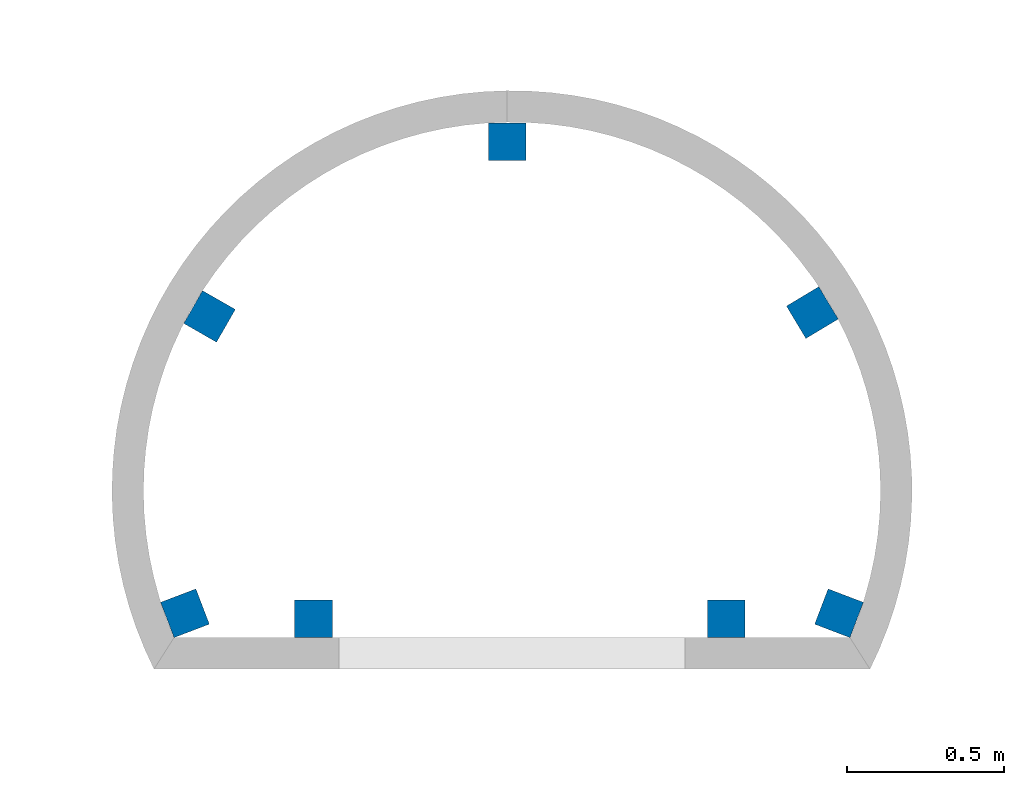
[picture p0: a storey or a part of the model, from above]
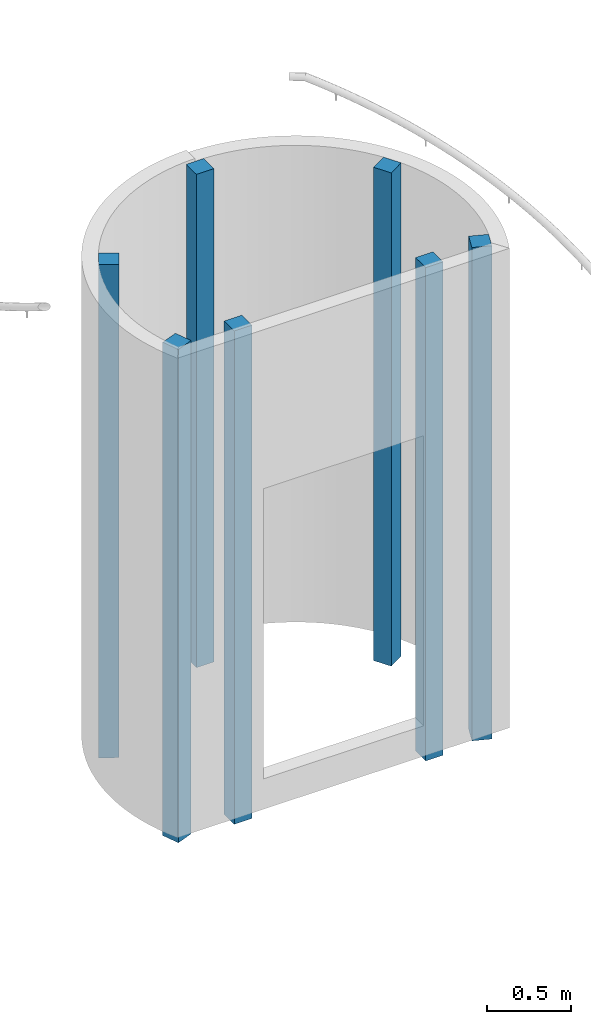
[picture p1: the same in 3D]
Properties of the parts of a building model (IFC4)

# File
Description: ViewDefinition [Design_Transfer_View, QuantityTakeOffAddOnView, SpaceBoundary2ndLevelAddOnView], ExchangeRequirement [Architecture], Option [Elements to export: Visible elements (on all stories)], Option [Partial Structure Display: Entire Model], Option [IFC Domain: All], Option [Structural Function: All Elements], Option [Convert Grid elements: On], Option [Convert IFC Annotations and Archicad 2D elements: Off], Option [Convert 2D symbols of Doors and Windows: Off], Option [Export geometries that Participates in Collision Detection only: Off], Option [Split complex elements: Off], Option [Material Preservation: Explode where necessary], Option [Elements in Solid Element Operations: Extruded/revolved], Option [Elements with junctions: Extruded/revolved without junctions], Option [IFC Model position: Survey Point and Project Origin], Option [Curtain Wall export mode: Container Element], Option [Railing export mode: Single Element], Option [Stair export mode: Container Element], Option [Properties To Export: All properties], Option [Space containment: On], Option [IFC Domain For Space Containment: All], Option [Geometry to type objects: Off], Option [Element Properties: Off], Option [Building Material Properties: Off], Option [Element Parameters: Off], Option [Component Parameters: Off], Option [IFC Base Quantities: On], Option [Door Window Parameters: On], Option [IFC Space boundaries: On], Option [Archicad Zone Categories as IFC Space classification data: Off], Option [Element Classifications: Off]
File name: C:\Users\micel\OneDrive\Dokumenty\ŠKOLA\!!4.LS!!\BAKALÁŘKA\Publikace\Nová složka\LES24-PST-ZZ-M3-Vyrobky.ifc
Time: 2024-05-22T15:31:04
Author: Architect
Organization: Building Designer Office
Written by: DDS_IFC v3.0
Made in: IFC file generated by Graphisoft Archicad 27.0.0 CZE FULL Windows version (IFC add-on version: 3001 CZE FULL).
Authorization: The authorising person

# IfcProject, Univerzitní lezecké centrum
Description: BIM projekt - bakalářská práce

# IfcSite, Exteriér
RefLatitude: 50, 1, 18, 339575; RefLongitude: 15, 46, 11, 568244; RefElevation: 221783 mm
Qto_SiteBaseQuantities - GrossPerimeter: 0 mm; GrossArea: 3562 m2

# IfcBuilding, Univerzitní lezecké centrum
Qto_BuildingBaseQuantities - GrossFloorArea: 0 m2

# IfcBuildingStorey (6)
In: Univerzitní lezecké centrum
Qto_BuildingStoreyBaseQuantities - GrossFloorArea: 0 m2
Name | Elevation (mm) | NetHeight (mm) = GrossHeight (mm)
2.NP | 3200 | 3200
4.NP | 9600 | 3200
3.NP | 6400 | 3200
Střecha | 12800 | 8000
1.NP | 0 | 3200
1.PP | -3350 | 3350

# IfcBeam: Benátské žaluzie 27 (14)
In: 1.NP
Type - PredefinedType: BEAM
Description: Venkovní žaluzie poháněné elektrickým motorkem, ovládání pomocí vypínače uvnitř prostoru lobby s posezením, lamely tvaru "C" o velikosti 65 mm, vodící lanka zajišťují směr pohybu lamel, barva černá Montováno do purenitových předomítkových boxů
Pset_BeamCommon - Status: EXISTING
Pset_ManufacturerOccurrence - AcquisitionDate: DD.MM.RRRR

# IfcBeam: Kačírková lišta 220 x 165 (9)
In: Střecha
Type - PredefinedType: BEAM
Description: Kačírková lišta - hliník tl. 2 mm, perforovaný pro umožnění průtoku vody, RAL 9007, úhel 78 stupňů, R.Š. 505 mm; Material: Hliníková kačírková lišta (2)
Pset_ManufacturerOccurrence - AcquisitionDate: DD.MM.RRRR
Qto_BeamBaseQuantities - CrossSectionArea: 0.00082048 m2
Pset_BeamCommon - Span: 4500 mm; Slope: 0 deg; IsExternal: no; Status: EXISTING; LoadBearing: yes; Reference: Kačírková lišta 220 x 165
Name | Length (mm) | OuterSurfaceArea (m2) | GrossSurfaceArea (m2) = NetSurfaceArea (m2) | GrossVolume (m3) = NetVolume (m3)
ZV08 | 4714.88 | 3.7068 | 3.70844 | 0.00387202
ZV08 | 5462.36 | 4.29446 | 4.2961 | 0.00448587
ZV08 | 5538.15 | 4.35405 | 4.35569 | 0.00454811
ZV08 | 10989.2 | 8.63963 | 8.64127 | 0.00902472
ZV08 | 16195.3 | 12.7326 | 12.7342 | 0.0133001
ZV08 | 16295.7 | 12.8116 | 12.8132 | 0.0133826
ZV08 | 5538.09 | 4.354 | 4.35564 | 0.00454806
ZV08 | 5460.56 | 4.29304 | 4.29468 | 0.00448439
ZV08 | 4712.68 | 3.70507 | 3.70671 | 0.00387021

# IfcBeam: Kačírková lišta vysoká 220 x 225, ZV07
In: Střecha
Type - PredefinedType: BEAM
Description: Kačírková lišta - hliník tl. 2 mm, perforovaný pro umožnění průtoku vody, RAL 9007, úhel 78 stupňů, R.Š. 565 mm; Material: Hliníková kačírková lišta (2)
Pset_BeamCommon - Span: 4500 mm; Slope: 0 deg; IsExternal: no; Status: EXISTING; LoadBearing: yes; Reference: Kačírková lišta vysoká 220 x 225
Pset_ManufacturerOccurrence - AcquisitionDate: DD.MM.RRRR
Qto_BeamBaseQuantities - Length: 16295 mm; CrossSectionArea: 0.00094048 m2; OuterSurfaceArea: 14.7664 m2; GrossSurfaceArea: 14.7683 m2; GrossVolume: 0.0153374 m3; NetSurfaceArea: 14.7683 m2; NetVolume: 0.0153374 m3

# IfcBeam: Kotvící bod záchytného systému 80 x 590 (12)
In: Střecha
Type - PredefinedType: BEAM
Description: Nerezový kotvicí bod pro ocelové konstrukce. Průměr sloupku je 12 mm. Instalace do předvrtaného otvoru v nosníku pomocí kontramatky. Pro použití jako koncový a zlomový bod v systémech s nerezovým lanem je nutné jej při délkách větších než 100 mm doplnit ztužující trubkou, délka kotvy 600 m Oky protaženo záchytné ocelové lano, délka 50 m; Material: Ocel - nerez (2)
Pset_ManufacturerOccurrence - AcquisitionDate: DD.MM.RRRR
Qto_BeamBaseQuantities - Length: 20 mm; CrossSectionArea: 0.0124075 m2; GrossVolume: 0.000246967 m3
Pset_BeamCommon - Span: 4500 mm; Slope: 0 deg; IsExternal: no; Status: EXISTING; LoadBearing: yes; Reference: Kotvící bod záchytného systému 80 x 590
Name | OuterSurfaceArea (m2) | GrossSurfaceArea (m2) = NetSurfaceArea (m2) | NetVolume (m3)
11 x OV27 | 0.0291858 | 0.0540008 | 0.000246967
OV27 | 0.029097 | 0.053912 | 0.000246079

# IfcBeam: Kruhová střešní vpusť 27 (2)
In: 3.NP
Type - PredefinedType: BEAM
Description: Vodorovná vpusť s integrovanou manžetou z TPO fólie, typ TW 110 V - DN 100 mm, vodorovné odvodní potrubí, tělo vpusti z polyamid PA6 s ochranným košem rozměry viz schéma: a=330, b=200, c=130, d=157, e=25 , f=238, g=47 mm
Reference - Referenční výrobek: https://www.topwet.cz/vodorovna-stresni-vpust-s-integrovanou-pvc-manzetou-p7
Pset_ManufacturerOccurrence - AcquisitionDate: DD.MM.RRRR
Pset_BeamCommon - Status: EXISTING

# IfcBeam: L profil 90x90x7 90 x 90 (8)
In: Střecha
Type - PredefinedType: BEAM
Description: L úhelník 90x90x7 mm - nerezový úhelník pro uchycení střešních oken, okno kotveno z bočních stran, úhelník kotven k betonové vrstvě na trapézovém plechu; Material: Ocel - nerez
Pset_BeamCommon - Span: 4500 mm; Slope: 12 deg; IsExternal: no; Status: EXISTING; LoadBearing: yes; Reference: L profil 90x90x7 90 x 90
Pset_ManufacturerOccurrence - AcquisitionDate: DD.MM.RRRR
Qto_BeamBaseQuantities - Length: 2019.13 mm; CrossSectionArea: 0.001211 m2; OuterSurfaceArea: 0.72 m2; GrossSurfaceArea: 0.722422 m2; GrossVolume: 0.002422 m3; NetSurfaceArea: 0.722422 m2; NetVolume: 0.002422 m3

# IfcBeam: Purenitový podomítkový box 195 x 302 (14)
In: 1.NP
Type - PredefinedType: BEAM
Description: Předomítkový purenitový box pro montáž venkovních žaluzií, tloušťka komplet purenitu 20 mm, R.Š. 505 mm, varianta pro omítnutí, kotveno montážní konzolou - úhleníkem L 100x100 mm (v rámci dodávky boxu), délka boxu 1250 mm; Material: Tepelná izolace - purenit (2), Hliník (2)
Pset_BeamCommon - Span: 4500 mm; Slope: 0 deg; IsExternal: no; Status: EXISTING; LoadBearing: yes; Reference: Purenitový podomítkový box 195 x 302
Pset_ManufacturerOccurrence - AcquisitionDate: DD.MM.RRRR
Qto_BeamBaseQuantities - Length: 1250 mm; CrossSectionArea: 0.0103491 m2; GrossVolume: 0.0129364 m3
Name | OuterSurfaceArea (m2) | GrossSurfaceArea (m2) = NetSurfaceArea (m2) | NetVolume (m3)
OV10 | 1.14941 | 1.17011 | 0.0117203
OV10 | 1.14885 | 1.16955 | 0.0117197
OV10 | 1.14929 | 1.16999 | 0.0117202
OV10 | 1.14908 | 1.16978 | 0.0117201
OV10 | 1.14916 | 1.16986 | 0.01172
OV10 | 1.14858 | 1.16928 | 0.0117195
OV10 | 1.14865 | 1.16935 | 0.0117195
OV10 | 1.14898 | 1.16968 | 0.0117198
OV10 | 1.14879 | 1.16949 | 0.0117197
OV10 | 1.14884 | 1.16953 | 0.0117198
OV10 | 1.14853 | 1.16923 | 0.0117195
OV10 | 1.14892 | 1.16962 | 0.0117198
OV10 | 1.14868 | 1.16938 | 0.0117196
OV10 | 1.14905 | 1.16975 | 0.0117199

# IfcBeam: Stojan na kola 02 27 (5)
In: 1.PP
Type - PredefinedType: BEAM
Description: Nerezový stojan na kola, sloupky zabetonovány pod zámkovou dlažbou, na 6 kol
Pset_BeamCommon - Status: EXISTING
Pset_ManufacturerOccurrence - AcquisitionDate: DD.MM.RRRR

# IfcBeam: Tlakový hasicí přístroj 24 (20)
Type - PredefinedType: BEAM
Description: Hasící přístroj 21A - práškový, objem hasiva 6kg, rozměry 190x530, s držákem a manometrem, zavěšený na zdi 600 mm nad zemí
Pset_BeamCommon - Status: EXISTING
Pset_ManufacturerOccurrence - AcquisitionDate: DD.MM.RRRR
Name | In
5 x OV01 | 1.PP
4 x OV01 | 1.NP
5 x OV01 | 2.NP
3 x OV01 | 3.NP
3 x OV01 | 4.NP

# IfcBeam: Zrcadlo 27 (2)
In: 1.PP
Type - PredefinedType: BEAM
Pset_ManufacturerOccurrence - AcquisitionDate: DD.MM.RRRR
Pset_BeamCommon - Status: EXISTING

# IfcBeam: Žebřík s klecí 24, ZV05
In: Střecha
Type - PredefinedType: BEAM
Description: Provozní žebřík pro přístup na pultovou střechu objektu, opatřen plošinou se zábradlím, výška žebříku vyšší než 3,0 m --> zádržný systém viz ZV05, vzdálenost příčlí 300 mm, rozteč štěřín 550 mm, návrh dle ČSN 74 3282 Pevné kovové žebříky pro stavby Ževřík kotven opřen o podlahu a kotven do svislé železobetonové stěny skrze systémové kotvy pro zamezení vzniku tepelných mostů
Pset_BeamCommon - Status: EXISTING
Pset_ManufacturerOccurrence - AcquisitionDate: DD.MM.RRRR

# IfcBuildingElementProxy: Lavice 24 (12)
Pset_BuildingElementProxyCommon - Status: EXISTING
Name | In | Description
8 x OV04 | 1.PP | Kovová lavice (š.d.v.) 450x1500x400 mm, dřevotřísková deska bílá lesklá s abs hranou, tloušťka desky 25 mm
2 x OV05 | 2.NP | Kovová lavice (š.d.v.) 450x1250x400 mm, dřevotřísková deska bílá lesklá s abs hranou, tloušťka desky 25 mm
2 x OV04 | 2.NP | Kovová lavice (š.d.v.) 450x1500x400 mm, dřevotřísková deska bílá lesklá s abs hranou, tloušťka desky 25 mm

# IfcBuildingElementProxy: Okap 27 (2)
In: Střecha
Description: Žlab - obdélníkový přůřez 150x200 mm, pozinkovaný lakovaný RAL 9007, lakované pozinkované háky RAL 9007 po délce 1 m
Pset_BuildingElementProxyCommon - Status: EXISTING

# IfcBuildingElementProxy: Okapová roura 27 (2)
In: Střecha
Description: Odvodňovací svod - čtvercový přůřez DN150 mm, pozinkovaný, délka 3,0 m, lakovaný RAL 9007, lakované pozinkované kotvy RAL 9007 po výšce 1 m a 0,5 m od spodního nebo vrchního ukončení svodu, kotva R.Š. 640 mm
Pset_BuildingElementProxyCommon - Status: EXISTING

# IfcBuildingElementProxy: Popelnice 27 (3)
In: 1.NP
Pset_BuildingElementProxyCommon - Status: EXISTING

# IfcBuildingElementProxy: Skříňky 24 (64)
Description: Kovová šatní skříňka, 300x400x2050 mm, otevíravé jednokřídlé dveře, větrání z čelní a zadní strany, se zámkem na klíč a žeton/10 kč, barva modrá
Pset_BuildingElementProxyCommon - Status: EXISTING
Name | In
20 x OV02 | 1.PP
20 x OV03 | 1.PP
12 x OV02 | 2.NP
12 x OV03 | 2.NP

# IfcBuildingElementProxy: Výtah 24, OV26
In: 1.NP
Description: Výtah s definováním přejezdu dole i nahoře by byl předmětem speciální dokumentace a konfigurace výtahového balíčku, který je v tomto případě kompletně specifický, nosné profily z nerezové oceli kotvené z boku do schodišťových ramen nesou opláštění z hliníku, uvinitř složeného kruhového prostoru by se nacházel výtah s velikostí min 1600x900 mm, aby mohl obsluhovat osoby se sníženou schopností pohybu, výtah obsluhuje všechna podlaží
Pset_BuildingElementProxyCommon - Status: EXISTING

# IfcColumn: Nerez ocel D50, ZV04
In: 4.NP
Type - PredefinedType: COLUMN
Description: Pevný zajišťovací systém pro provozní žebřík ZV05, pohyb zachycovače pádu zajištěn pomocí kolejnice s karabinou, provedeno dle ČSN EN 353-1+A1 Prostředky ochrany osob proti pádu - Pohyblivé zachycovače pádu vetně zajišťovacího vedení - část1, umístěn uprostřed příčlí žebříku; Material: Nerez ocel
Pset_ManufacturerOccurrence - AcquisitionDate: DD.MM.RRRR
Qto_ColumnBaseQuantities - Length: 3700 mm; CrossSectionArea: 0.00196351 m2; OuterSurfaceArea: 0.57458 m2; GrossSurfaceArea: 0.57833 m2; GrossVolume: 0.00693755 m3; NetSurfaceArea: 0 m2; NetVolume: 0.00693755 m3
Pset_ColumnCommon - Slope: 90 deg; Status: EXISTING; LoadBearing: yes; Reference: Nerez ocel D50

# IfcColumn: Uživatelský profil 120 x 120 (35)
Type - PredefinedType: COLUMN
Material: OBECNÉ - HRUBÉ STAVEBNÍ KONSTRUKCE
Pset_ColumnCommon - Slope: 90 deg; Status: EXISTING; LoadBearing: yes; Reference: Uživatelský profil 120 x 120
Pset_ManufacturerOccurrence - AcquisitionDate: DD.MM.RRRR
Qto_ColumnBaseQuantities - CrossSectionArea: 0.0144 m2; NetSurfaceArea: 0 m2
Name | In | Length (mm) | OuterSurfaceArea (m2) | GrossSurfaceArea (m2) | GrossVolume (m3) = NetVolume (m3)
S006 | 1.PP | 3450 | 1.58301 | 1.59741 | 0.0496634
S006 | 1.PP | 3450 | 1.64053 | 1.65493 | 0.0496776
S007 | 1.PP | 3450 | 1.656 | 1.6704 | 0.04968
S006 | 1.PP | 3450 | 1.656 | 1.6704 | 0.04968
S008 | 1.PP | 3450 | 1.656 | 1.6704 | 0.04968
S006 | 1.PP | 3450 | 1.24177 | 1.25617 | 0.0496663
S006 | 1.PP | 3450 | 1.24176 | 1.25616 | 0.0496656
S006 | 1.NP | 3200 | 1.43284 | 1.46162 | 0.0460389
S006 | 1.NP | 3200 | 1.536 | 1.5648 | 0.04608
S006 | 1.NP | 3200 | 1.52165 | 1.55045 | 0.0460777
S007 | 1.NP | 3200 | 1.536 | 1.5648 | 0.04608
S006 | 1.NP | 3200 | 1.15178 | 1.18057 | 0.0460668
S006 | 1.NP | 3200 | 1.15181 | 1.1806 | 0.0460684
S008 | 1.NP | 3200 | 1.536 | 1.5648 | 0.04608
S006 | 2.NP | 3200 | 1.43282 | 1.4616 | 0.0460389
S006 | 2.NP | 3200 | 1.536 | 1.5648 | 0.04608
S007 | 2.NP | 3200 | 1.536 | 1.5648 | 0.04608
S008 | 2.NP | 3200 | 1.536 | 1.5648 | 0.04608
S006 | 2.NP | 3200 | 1.15197 | 1.18076 | 0.0460783
S006 | 2.NP | 3200 | 1.15195 | 1.18075 | 0.046077
S006 | 2.NP | 3200 | 1.52165 | 1.55045 | 0.0460777
S006 | 3.NP | 3200 | 1.536 | 1.5648 | 0.04608
S006 | 3.NP | 3200 | 1.43274 | 1.46152 | 0.0460391
S006 | 3.NP | 3200 | 1.52165 | 1.55045 | 0.0460777
S007 | 3.NP | 3200 | 1.536 | 1.5648 | 0.04608
2 x S006 | 3.NP | 3200 | 1.15178 | 1.18057 | 0.0460666
S008 | 3.NP | 3200 | 1.536 | 1.5648 | 0.04608
2 x S006 | 4.NP | 2700 | 0.971812 | 1.0006 | 0.0388687
S006 | 4.NP | 2700 | 1.23888 | 1.26767 | 0.038867
S006 | 4.NP | 2700 | 1.28389 | 1.31269 | 0.0388781
S006 | 4.NP | 2700 | 1.296 | 1.3248 | 0.03888
S007 | 4.NP | 2700 | 1.296 | 1.3248 | 0.03888
S008 | 4.NP | 2700 | 1.296 | 1.3248 | 0.03888

# IfcCovering: Oplechování atiky 569 x 114, KV01
In: 4.NP
Type - PredefinedType: CEILING
Description: Oplechování atiky pozinkovaným lakovaným plechem, tl. 0,6 mm, R.Š. 770mm, délka 26, 389 m, uchyceno za zatahovací plechy - kotvení bez perforace, barva RAL9007, svislé drážky v obloucích dle zkušenosti provádění dodavatele; Material: Hliník
Pset_CoveringCommon - Status: EXISTING
Pset_ManufacturerOccurrence - AcquisitionDate: DD.MM.RRRR
Qto_CoveringBaseQuantities - Width: 568.723 mm; GrossArea: 14.3441 m2; NetArea: 0 m2

# IfcCovering: Závětrná lišta 174 x 60 (2)
In: Střecha
Type - PredefinedType: CEILING
Description: Závětrná lišta z poplastovaného plechu z PVC, šedá, pro ukončení povlakové hydroizolace na pultové střeše, izolace k liště napojena horkovzdušným svarem, RAL 9007, tl. 1 mm; Material: Hliník, Hydroizolace - TPO fólie
Pset_ManufacturerOccurrence - AcquisitionDate: DD.MM.RRRR
Pset_CoveringCommon - IsExternal: no; Status: EXISTING
Qto_CoveringBaseQuantities - Width: 174.227 mm; GrossArea: 1.39096 m2; NetArea: 1.39096 m2

# IfcCurtainWall: Typ lehkého obvodového pláště (2)
In: 3.NP
Description: Lehký obvodový plášť, výška 2500, délka 4500 mm, zasklení bezpečnostním sklem, barva rámu RAL 6019, otočné dveře uprostřed modulu
Pset_CurtainWallCommon - Status: EXISTING
Pset_ManufacturerOccurrence - AcquisitionDate: DD.MM.RRRR
Qto_CurtainWallQuantities - Width: 300 mm; Length: 4500.17 mm
Name | Height (mm) | GrossSideArea (m2) = NetSideArea (m2)
LOP04 | 2000 | 9.00033
LOP06 | 2500 | 11.2504

# IfcDiscreteAccessory: Vnitřní malba, OV07
In: 4.NP
Description: Logo univerzity Pardubice - dle výrobní dokumentace dodavatele; Material: Vnitřní malba
Pset_ManufacturerOccurrence - AcquisitionDate: DD.MM.RRRR
Pset_ElementComponentCommon - Status: EXISTING

# IfcMember: 50 x 100 (8)
In: 3.NP
Material: Hliník
Qto_MemberBaseQuantities - CrossSectionArea: 0.005 m2
Pset_ManufacturerOccurrence - AcquisitionDate: DD.MM.RRRR
Name | Length (mm) | OuterSurfaceArea (m2) | GrossSurfaceArea (m2) | GrossVolume (m3) = NetVolume (m3)
RS026 | 1552.16 | 0.465648 | 0.475648 | 0.00776081
RS026 | 1542.16 | 0.462649 | 0.472649 | 0.00771081
RT031 | 1342.32 | 0.402696 | 0.412696 | 0.0067116
RT031 | 1332.15 | 0.399645 | 0.409645 | 0.00666075
2 x RS026 | 342.584 | 0.102775 | 0.112775 | 0.00171292
2 x RS026 | 1880 | 0.564 | 0.574 | 0.0094

# IfcMember: 60 x 120 (13)
In: 3.NP
Material: Hliník
Pset_ManufacturerOccurrence - AcquisitionDate: DD.MM.RRRR
Qto_MemberBaseQuantities - CrossSectionArea: 0.0072 m2
Name | Length (mm) | OuterSurfaceArea (m2) | GrossSurfaceArea (m2) | GrossVolume (m3) = NetVolume (m3)
2 x RO246 | 1745.17 | 0.62826 | 0.64266 | 0.0125652
2 x RO246 | 1970 | 0.7092 | 0.7236 | 0.014184
2 x RO246 | 1745 | 0.6282 | 0.6426 | 0.012564
2 x RO246 | 470 | 0.1692 | 0.1836 | 0.003384
RO246 | 1720.17 | 0.61926 | 0.63366 | 0.0123852
RO246 | 1000 | 0.36 | 0.3744 | 0.0072
RO246 | 1720 | 0.6192 | 0.6336 | 0.012384
2 x RO246 | 1940 | 0.6984 | 0.7128 | 0.013968

# IfcMember: Rám obrysu 60 x 200 (3)
In: 3.NP
Material: Hliník
Pset_ManufacturerOccurrence - AcquisitionDate: DD.MM.RRRR
Qto_MemberBaseQuantities - CrossSectionArea: 0.012 m2
Name | Length (mm) | OuterSurfaceArea (m2) | GrossSurfaceArea (m2) | GrossVolume (m3) = NetVolume (m3)
RO264 | 1720.17 | 0.894487 | 0.918487 | 0.020642
RO262 | 1720 | 0.8944 | 0.9184 | 0.02064
RO263 | 1000 | 0.52 | 0.544 | 0.012

# IfcMember: Trámky 50 x 75, RT031
In: 3.NP
Material: Hliník
Pset_ManufacturerOccurrence - AcquisitionDate: DD.MM.RRRR
Qto_MemberBaseQuantities - Length: 950 mm; CrossSectionArea: 0.00375 m2; OuterSurfaceArea: 0.2375 m2; GrossSurfaceArea: 0.245 m2; GrossVolume: 0.0035625 m3; NetVolume: 0.0035625 m3

# IfcOpeningElement (5)
Qto_OpeningElementBaseQuantities - Depth: 100 mm; Height: 2100 mm; Width: 1098 mm; Area: 2.3058 m2; Volume: 0 m3
Name | In
 | 1.PP
 | 1.NP
 | 2.NP
 | 3.NP
 | 4.NP

# IfcPlate: 1000 x 5 x 20, PD010
In: 3.NP
Type - PredefinedType: CURTAIN_PANEL
Material: Hliník, Sklo, Ocel - nerez
Pset_ManufacturerOccurrence - AcquisitionDate: DD.MM.RRRR; SerialNumber: ne
Pset_PrecastConcreteElementFabrication - SerialNumber: ne
Qto_PlateBaseQuantities - Width: 950 mm; Perimeter: 5850 mm; GrossArea: 2.025 m2; NetArea: 1.87625 m2; GrossVolume: 0.0405 m3; NetVolume: 0.037525 m3

# IfcPlate: 1750 x 5 x 20 (2)
In: 3.NP
Type - PredefinedType: CURTAIN_PANEL
Material: Sklo
Pset_ManufacturerOccurrence - AcquisitionDate: DD.MM.RRRR
Name | Width (mm) | Perimeter (mm) | GrossArea (m2) | NetArea (m2) | GrossVolume (m3) | NetVolume (m3)
Panely-Okno-019 | 1665.17 | 7160.33 | 3.40748 | 3.18879 | 0.0681496 | 0.0637759
Panely-Okno-019 | 1665 | 7160 | 3.40715 | 3.18847 | 0.068143 | 0.0637695

# IfcPlate: 5 x 2000 x 20, Panely-Okno-019
In: 3.NP
Type - PredefinedType: CURTAIN_PANEL
Material: Sklo
Pset_ManufacturerOccurrence - AcquisitionDate: DD.MM.RRRR
Qto_PlateBaseQuantities - Width: 1665 mm; Perimeter: 7090 mm; GrossArea: 3.3468 m2; NetArea: 3.1302 m2; GrossVolume: 0.066936 m3; NetVolume: 0.062604 m3

# IfcPlate: 5 x 30 x 20 (4)
In: 3.NP
Type - PredefinedType: CURTAIN_PANEL
Pset_ManufacturerOccurrence - AcquisitionDate: DD.MM.RRRR
Name | Material | Width (mm) | Perimeter (mm) | GrossArea (m2) | NetArea (m2) | GrossVolume (m3) | NetVolume (m3)
Panely-Okno-019 | Sklo | 1665.17 | 4160.33 | 0.819729 | 0.691044 | 0.0163946 | 0.0138209
Panely-Okno-019 | Sklo | 950 | 2730 | 0.48 | 0.39425 | 0.0096 | 0.007885
Panely-Okno-019 | Sklo | 1665.17 | 7090.33 | 3.34712 | 3.13051 | 0.0669425 | 0.0626103
PD010 | Hliník, Sklo, Ocel - nerez | 950 | 5780 | 1.99 | 1.843 | 0.0398 | 0.03686 | Pset_PrecastConcreteElementFabrication - SerialNumber: ne; Pset_ManufacturerOccurrence - SerialNumber: ne

# IfcPlate: 5 x 500 x 20, Panely-Okno-019
In: 3.NP
Type - PredefinedType: CURTAIN_PANEL
Material: Sklo
Pset_ManufacturerOccurrence - AcquisitionDate: DD.MM.RRRR
Qto_PlateBaseQuantities - Width: 1665 mm; Perimeter: 4160 mm; GrossArea: 0.81965 m2; NetArea: 0.690975 m2; GrossVolume: 0.016393 m3; NetVolume: 0.0138195 m3

# IfcRailing: Typ zábradlí (9)
Type - PredefinedType: HANDRAIL
Pset_ManufacturerOccurrence - AcquisitionDate: DD.MM.RRRR
Pset_RailingCommon - Status: EXISTING
Name | In | Description | Material | Length (mm)
ZV01 | 1.PP | Nerezové madlo schodiště - kruhový průřez o průměru 50 mm, kotveno 7 kotvami s kruhovým štítem, kotveno šrouby do svislé železobetonové stěny v oblouku, vodorovný přesah na začátku a konci zábralí 200 mm | Nerez ocel (3), Ocel - nerez | 5516.01
ZV01 | 1.PP | Nerezové madlo schodiště - kruhový průřez o průměru 50 mm, kotveno 7 kotvami s kruhovým štítem, kotveno šrouby do svislé železobetonové stěny v oblouku, vodorovný přesah na začátku a konci zábralí 200 mm | Nerez ocel (3), Ocel - nerez | 5304.73
ZV01 | 1.NP | Nerezové madlo schodiště - kruhový průřez o průměru 50 mm, kotveno 7 kotvami s kruhovým štítem, kotveno šrouby do svislé železobetonové stěny v oblouku, vodorovný přesah na začátku a konci zábralí 200 mm | Nerez ocel (3), Ocel - nerez | 5516.01
ZV01 | 1.NP | Nerezové madlo schodiště - kruhový průřez o průměru 50 mm, kotveno 7 kotvami s kruhovým štítem, kotveno šrouby do svislé železobetonové stěny v oblouku, vodorovný přesah na začátku a konci zábralí 200 mm | Nerez ocel (3), Ocel - nerez | 5304.73
ZV01 | 2.NP | Nerezové madlo schodiště - kruhový průřez o průměru 50 mm, kotveno 7 kotvami s kruhovým štítem, kotveno šrouby do svislé železobetonové stěny v oblouku, vodorovný přesah na začátku a konci zábralí 200 mm | Nerez ocel (3), Ocel - nerez | 5516.01
ZV01 | 2.NP | Nerezové madlo schodiště - kruhový průřez o průměru 50 mm, kotveno 7 kotvami s kruhovým štítem, kotveno šrouby do svislé železobetonové stěny v oblouku, vodorovný přesah na začátku a konci zábralí 200 mm | Nerez ocel (3), Ocel - nerez | 5304.73
ZV02 | 3.NP | Zábradlí nerez+skleněné panely, po segmentech širokých 1000 mm, skleněné panely kotveny ze spodního a horního okraje, výška podního vodorovného prvku 100 mm od podlahy, madlo ve cýšce 1000 mm, madlo kruhového průřezu z nerezové oceli průměru 50 mm, kotveno do podlahy | Ocel - nerez (22), Nerez ocel (17), Sklo (15), OBECNÉ - HRUBÉ STAVEBNÍ KONSTRUKCE (15) | 14742.2
ZV01 | 3.NP | Nerezové madlo schodiště - kruhový průřez o průměru 50 mm, kotveno 7 kotvami s kruhovým štítem, kotveno šrouby do svislé železobetonové stěny v oblouku, vodorovný přesah na začátku a konci zábralí 200 mm | Nerez ocel (3), Ocel - nerez | 5304.73
ZV01 | 3.NP | Nerezové madlo schodiště - kruhový průřez o průměru 50 mm, kotveno 7 kotvami s kruhovým štítem, kotveno šrouby do svislé železobetonové stěny v oblouku, vodorovný přesah na začátku a konci zábralí 200 mm | Nerez ocel (3), Ocel - nerez | 5516.01

# IfcSanitaryTerminal: Dining Table Round 17 (10)
In: 1.NP
Description: Stolová soustava - nerezové nohy židlí i stolu, stolní deska ze dřeva s hranou z abs, židle s textilním sedátkem, 3 židle
Pset_ManufacturerOccurrence - AcquisitionDate: DD.MM.RRRR

# IfcSanitaryTerminal: Veřejná koupelnová kabinka 27 (6)
Pset_ManufacturerOccurrence - AcquisitionDate: DD.MM.RRRR
Name | In | Description
2 x OV22 | 1.PP | WC kabinka v provedení pro dva zařizovací předměty, osazena kováním a WC zámkem se zobrazením obsazenosti pomocí zelené/ červené, kotveno do podlahy, opřeno o podhled
2 x OV24 | 2.NP | WC kabinka v provedení pro jeden zařizovací předmět, osazena kováním a WC zámkem se zobrazením obsazenosti pomocí zelené/ červené, kotveno do podlahy, opřeno o podhled
2 x OV23 | 2.NP | WC kabinka v provedení čelní strana s dveřmi, osazena kováním a WC zámkem se zobrazením obsazenosti pomocí zelené/červené, kotveno do podlahy, opřeno o podhled

# IfcSlab: Dřevo - nábytek 35 (5)
In: 1.NP
Type - PredefinedType: FLOOR
Description: Deska recepčního pultu; Material: Dřevo - nábytek 35 mm
Pset_ManufacturerOccurrence - AcquisitionDate: DD.MM.RRRR
Pset_SlabCommon - Status: EXISTING; LoadBearing: no
Qto_SlabBaseQuantities - Width: 35 mm; Dřevo - nábytek, Width: 35 mm
Name | Perimeter (mm) | GrossArea (m2) = NetArea (m2) | GrossVolume (m3) = NetVolume (m3)
TV01 | 12800.8 | 4.55796 | 0.159529
2 x TV01 | 4904.06 | 1.27807 | 0.0447324
2 x TV01 | 6300 | 1.8 | 0.063

# IfcSlab: Hliníková kačírková lišta 220 (2)
In: Střecha
Type - PredefinedType: ROOF
Description: Kačírková lišta - hliník tl. 2 mm, RAL 9007, úhel 78 stupňů, R.Š. 565 mm
Pset_SlabCommon - Status: EXISTING; LoadBearing: yes
Pset_ManufacturerOccurrence - AcquisitionDate: DD.MM.RRRR
Qto_SlabBaseQuantities - Width: 220.083 mm; Hliníková kačírková lišta, Width: 220.083 mm
Name | Material | Perimeter (mm) | GrossArea (m2) | NetArea (m2) | GrossVolume (m3) | NetVolume (m3)
ZV06 | Hliníková kačírková lišta | 43600.3 | 0.0874336 | 0.0874336 | 0.0192404 | 0.0192404
ZV06 | Hliníková kačírková lišta 220.083 mm | 22462.5 | 31.3785 | 0.0454921 | 6.90589 | 0.0100121

# IfcWall: Dřevo - nábytek 100 (4)
In: 1.NP
Material: Dřevo - nábytek 100 mm
Pset_WallCommon - IsExternal: no; Status: EXISTING; LoadBearing: no
Pset_ManufacturerOccurrence - AcquisitionDate: DD.MM.RRRR
Qto_WallBaseQuantities - Width: 100 mm; Dřevo - nábytek, Width: 100 mm
Name | Description | Length (mm) | Height (mm) | GrossFootprintArea (m2) = NetFootprintArea (m2) | GrossSideArea (m2) = NetSideArea (m2) | GrossVolume (m3) = NetVolume (m3)
Z063 | Recepční pul | 3950.39 | 920 | 0.400038 | 3.47758 | 0.356177
TV01 | Dřevěný recepční pult, dle výrobní dokumentace dodavatele, dřevěné desky s 1 ABS hranou, svislé "nohy" pultu opatřeny betonovou stěrkou, vodorovné desky bílé lesklé | 2449.98 | 1320 | 0.25 | 3.20798 | 0.320798
2 x TV01 | Dřevěný recepční pult, dle výrobní dokumentace dodavatele, dřevěné desky s 1 ABS hranou, svislé "nohy" pultu opatřeny betonovou stěrkou, vodorovné desky bílé lesklé | 850 | 890 | 0.085 | 0.7565 | 0.07565

# IfcWall: Sklo 100 (15)
Pset_ManufacturerOccurrence - AcquisitionDate: DD.MM.RRRR
Pset_WallCommon - Status: EXISTING; LoadBearing: yes
Qto_WallBaseQuantities - Width: 100 mm; Sklo, Width: 100 mm
Name | In | Material | Length (mm) | Height (mm) | GrossFootprintArea (m2) = NetFootprintArea (m2) | GrossSideArea (m2) | NetSideArea (m2) | GrossVolume (m3) | NetVolume (m3)
Z053 | 1.PP | Sklo 100 mm | 2434.11 | 3470 | 0.249155 | 8.64545 | 8.64545 | 0.864518 | 0.864518
Z054 | 1.PP | Sklo 100 mm | 2465.77 | 3450 | 0.252293 | 8.70416 | 8.70416 | 0.870412 | 0.870412
Z053 | 1.PP | Sklo 100 mm | 2209.59 | 3350 | 0.209854 | 7.02525 | 4.71945 | 0.703011 | 0.472431
Z054 | 1.NP | Sklo 100 mm | 2449.9 | 3200 | 0.250718 | 8.02286 | 8.02286 | 0.802247 | 0.802247
Z055 | 1.NP | Sklo 100 mm | 2449.97 | 3200 | 0.250694 | 8.02256 | 8.02256 | 0.80222 | 0.80222
Z053 | 1.NP | Sklo 100 mm | 2209.59 | 3320 | 0.212388 | 6.84049 | 4.53469 | 0.671574 | 0.440995
Z056 | 2.NP | Sklo 100 mm | 2449.95 | 3220 | 0.250723 | 8.02401 | 8.02401 | 0.802313 | 0.802313
Z053 | 2.NP | Sklo 100 mm | 2209.57 | 3320 | 0.221132 | 6.84402 | 4.53822 | 0.672449 | 0.441869
Z057 | 2.NP | Sklo 100 mm | 2449.97 | 3200 | 0.250694 | 8.02206 | 8.02206 | 0.802171 | 0.802171
Z059 | 3.NP | Sklo 100 mm | 2449.97 | 3200 | 0.250694 | 8.02206 | 8.02206 | 0.80217 | 0.80217
Z058 | 3.NP | Sklo 100 mm | 2449.9 | 3200 | 0.250718 | 8.02286 | 8.02286 | 0.802297 | 0.802297
Z053 | 3.NP | Sklo 100 mm | 2209.59 | 3200 | 0.212345 | 6.71173 | 4.40593 | 0.671572 | 0.440992
Z061 | 4.NP | Sklo | 2465.77 | 2720 | 0.252293 | 6.86241 | 6.86241 | 0.686238 | 0.686238
Z060 | 4.NP | Sklo | 2434.11 | 2720 | 0.249155 | 6.77723 | 6.77723 | 0.677702 | 0.677702
Z053 | 4.NP | Sklo 100 mm | 2209.59 | 2820 | 0.209865 | 5.91379 | 3.60799 | 0.591788 | 0.361208

# IfcWindow: Kruhový vypuklý světlík 24 (3)
In: 4.NP
OverallHeight: 100 mm
Pset_ManufacturerOccurrence - AcquisitionDate: DD.MM.RRRR
Pset_WindowCommon - ThermalTransmittance: 0; Status: EXISTING
Name | Description | OverallWidth (mm)
2 x O06 | Kopulovité PET-G + PMA zasklení, hliníkové okno, barva rámu Šedá, RAL 9007, způsob otvírání - pevný | 1500
O07 | Kopulovité PET-G + PMA zasklení, hliníkové okno, barva rámu Šedá, RAL 9007, způsob otevírání - pevné | 2000
